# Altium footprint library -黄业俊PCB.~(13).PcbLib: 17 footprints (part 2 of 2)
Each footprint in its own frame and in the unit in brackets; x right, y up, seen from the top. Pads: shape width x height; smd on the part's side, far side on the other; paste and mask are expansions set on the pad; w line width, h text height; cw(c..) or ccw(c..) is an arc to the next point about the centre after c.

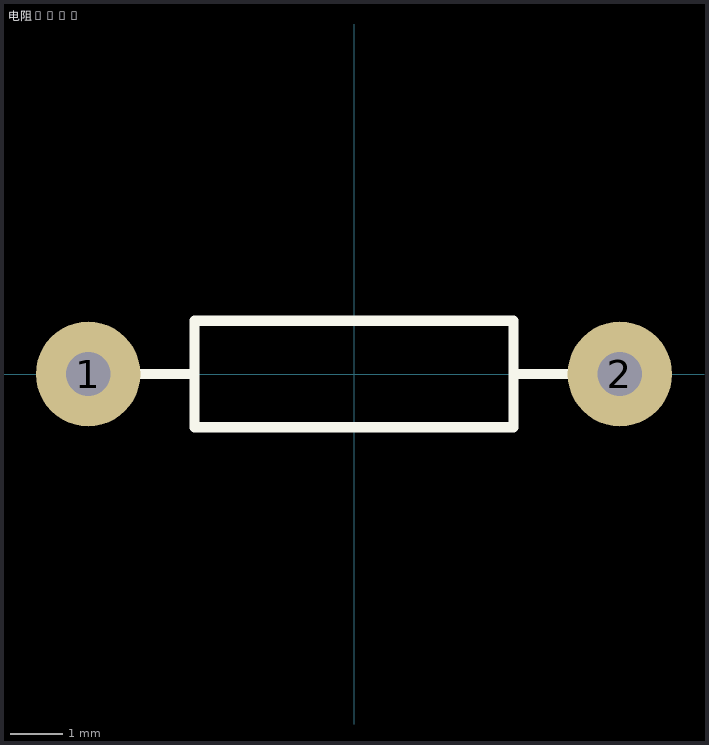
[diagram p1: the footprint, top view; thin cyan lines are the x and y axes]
## 电阻1/4W [mm]
pads (2):
  round 2 hole 0.85: 1(-5.08,0) 2(5.08,0)
Top Overlay:
  lines w0.2: -4.064,0 -3.048,0 ; 3.048,0 4.064,0 ; -3.048,-1.016 -3.048,1.016 3.048,1.016 3.048,-1.016 -3.048,-1.016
